VERSION 5.7 ;
  NOWIREEXTENSIONATPIN ON ;
  DIVIDERCHAR "/" ;
  BUSBITCHARS "[]" ;
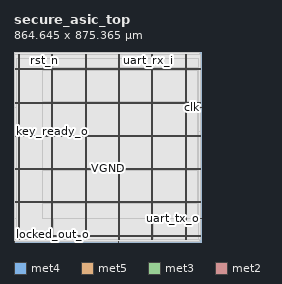
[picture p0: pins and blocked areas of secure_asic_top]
MACRO secure_asic_top
  CLASS BLOCK ;
  FOREIGN secure_asic_top ;
  ORIGIN 0.000 0.000 ;
  SIZE 864.645 BY 875.365 ;
  PIN VGND
    DIRECTION INOUT ;
    USE GROUND ;
    PORT
      LAYER met4 ;
        RECT 24.340 10.640 25.940 862.480 ;
    END
    PORT
      LAYER met4 ;
        RECT 177.940 10.640 179.540 862.480 ;
    END
    PORT
      LAYER met4 ;
        RECT 331.540 10.640 333.140 862.480 ;
    END
    PORT
      LAYER met4 ;
        RECT 485.140 10.640 486.740 862.480 ;
    END
    PORT
      LAYER met4 ;
        RECT 638.740 10.640 640.340 862.480 ;
    END
    PORT
      LAYER met4 ;
        RECT 792.340 10.640 793.940 862.480 ;
    END
    PORT
      LAYER met5 ;
        RECT 5.280 30.030 859.060 31.630 ;
    END
    PORT
      LAYER met5 ;
        RECT 5.280 183.210 859.060 184.810 ;
    END
    PORT
      LAYER met5 ;
        RECT 5.280 336.390 859.060 337.990 ;
    END
    PORT
      LAYER met5 ;
        RECT 5.280 489.570 859.060 491.170 ;
    END
    PORT
      LAYER met5 ;
        RECT 5.280 642.750 859.060 644.350 ;
    END
    PORT
      LAYER met5 ;
        RECT 5.280 795.930 859.060 797.530 ;
    END
  END VGND
  PIN VPWR
    DIRECTION INOUT ;
    USE POWER ;
    PORT
      LAYER met4 ;
        RECT 21.040 10.640 22.640 862.480 ;
    END
    PORT
      LAYER met4 ;
        RECT 174.640 10.640 176.240 862.480 ;
    END
    PORT
      LAYER met4 ;
        RECT 328.240 10.640 329.840 862.480 ;
    END
    PORT
      LAYER met4 ;
        RECT 481.840 10.640 483.440 862.480 ;
    END
    PORT
      LAYER met4 ;
        RECT 635.440 10.640 637.040 862.480 ;
    END
    PORT
      LAYER met4 ;
        RECT 789.040 10.640 790.640 862.480 ;
    END
    PORT
      LAYER met5 ;
        RECT 5.280 26.730 859.060 28.330 ;
    END
    PORT
      LAYER met5 ;
        RECT 5.280 179.910 859.060 181.510 ;
    END
    PORT
      LAYER met5 ;
        RECT 5.280 333.090 859.060 334.690 ;
    END
    PORT
      LAYER met5 ;
        RECT 5.280 486.270 859.060 487.870 ;
    END
    PORT
      LAYER met5 ;
        RECT 5.280 639.450 859.060 641.050 ;
    END
    PORT
      LAYER met5 ;
        RECT 5.280 792.630 859.060 794.230 ;
    END
  END VPWR
  PIN clk
    DIRECTION INPUT ;
    USE SIGNAL ;
    ANTENNAGATEAREA 1.286700 ;
    ANTENNADIFFAREA 0.434700 ;
    PORT
      LAYER met3 ;
        RECT 860.645 618.840 864.645 619.440 ;
    END
  END clk
  PIN fifo_overflow_o
    DIRECTION OUTPUT TRISTATE ;
    USE SIGNAL ;
    ANTENNADIFFAREA 0.795200 ;
    PORT
      LAYER met2 ;
        RECT 483.090 0.000 483.370 4.000 ;
    END
  END fifo_overflow_o
  PIN key_ready_o
    DIRECTION OUTPUT TRISTATE ;
    USE SIGNAL ;
    ANTENNADIFFAREA 0.795200 ;
    PORT
      LAYER met3 ;
        RECT 0.000 510.040 4.000 510.640 ;
    END
  END key_ready_o
  PIN locked_out_o
    DIRECTION OUTPUT TRISTATE ;
    USE SIGNAL ;
    ANTENNADIFFAREA 0.795200 ;
    PORT
      LAYER met2 ;
        RECT 0.090 0.000 0.370 4.000 ;
    END
  END locked_out_o
  PIN rst_n
    DIRECTION INPUT ;
    USE SIGNAL ;
    ANTENNAGATEAREA 0.196500 ;
    PORT
      LAYER met2 ;
        RECT 138.550 871.365 138.830 875.365 ;
    END
  END rst_n
  PIN uart_rx_i
    DIRECTION INPUT ;
    USE SIGNAL ;
    ANTENNAGATEAREA 0.196500 ;
    PORT
      LAYER met2 ;
        RECT 621.550 871.365 621.830 875.365 ;
    END
  END uart_rx_i
  PIN uart_tx_o
    DIRECTION OUTPUT TRISTATE ;
    USE SIGNAL ;
    ANTENNADIFFAREA 0.445500 ;
    PORT
      LAYER met3 ;
        RECT 860.645 108.840 864.645 109.440 ;
    END
  END uart_tx_o
  OBS
      LAYER li1 ;
        RECT 5.520 10.795 858.820 862.325 ;
      LAYER met1 ;
        RECT 0.070 10.640 858.820 862.480 ;
      LAYER met2 ;
        RECT 0.100 871.085 138.270 871.365 ;
        RECT 139.110 871.085 621.270 871.365 ;
        RECT 622.110 871.085 856.890 871.365 ;
        RECT 0.100 4.280 856.890 871.085 ;
        RECT 0.650 4.000 482.810 4.280 ;
        RECT 483.650 4.000 856.890 4.280 ;
      LAYER met3 ;
        RECT 4.000 619.840 860.645 862.405 ;
        RECT 4.000 618.440 860.245 619.840 ;
        RECT 4.000 511.040 860.645 618.440 ;
        RECT 4.400 509.640 860.645 511.040 ;
        RECT 4.000 109.840 860.645 509.640 ;
        RECT 4.000 108.440 860.245 109.840 ;
        RECT 4.000 10.715 860.645 108.440 ;
      LAYER met4 ;
        RECT 13.175 11.735 20.640 847.105 ;
        RECT 23.040 11.735 23.940 847.105 ;
        RECT 26.340 11.735 174.240 847.105 ;
        RECT 176.640 11.735 177.540 847.105 ;
        RECT 179.940 11.735 327.840 847.105 ;
        RECT 330.240 11.735 331.140 847.105 ;
        RECT 333.540 11.735 481.440 847.105 ;
        RECT 483.840 11.735 484.740 847.105 ;
        RECT 487.140 11.735 635.040 847.105 ;
        RECT 637.440 11.735 638.340 847.105 ;
        RECT 640.740 11.735 788.640 847.105 ;
        RECT 791.040 11.735 791.940 847.105 ;
        RECT 794.340 11.735 848.865 847.105 ;
      LAYER met5 ;
        RECT 130.300 799.130 845.820 804.900 ;
        RECT 130.300 645.950 845.820 791.030 ;
        RECT 130.300 492.770 845.820 637.850 ;
        RECT 130.300 339.590 845.820 484.670 ;
        RECT 130.300 186.410 845.820 331.490 ;
        RECT 130.300 106.300 845.820 178.310 ;
  END
END secure_asic_top
END LIBRARY

